VERSION 5.7 ;
  NOWIREEXTENSIONATPIN ON ;
  DIVIDERCHAR "/" ;
  BUSBITCHARS "[]" ;
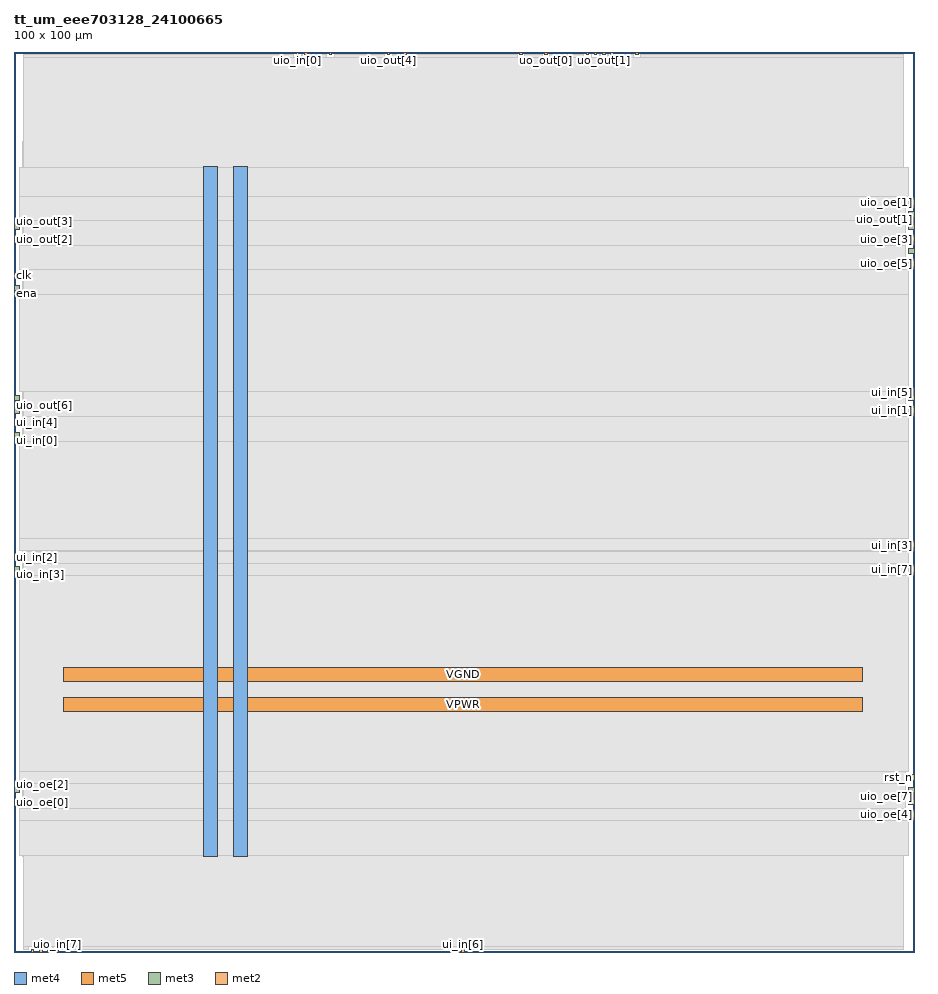
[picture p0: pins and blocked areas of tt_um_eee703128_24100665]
MACRO tt_um_eee703128_24100665
  CLASS BLOCK ;
  FOREIGN tt_um_eee703128_24100665 ;
  ORIGIN 0.000 0.000 ;
  SIZE 100.000 BY 100.000 ;
  PIN VGND
    DIRECTION INOUT ;
    USE GROUND ;
    PORT
      LAYER met4 ;
        RECT 24.340 10.640 25.940 87.280 ;
    END
    PORT
      LAYER met5 ;
        RECT 5.520 30.030 94.300 31.630 ;
    END
  END VGND
  PIN VPWR
    DIRECTION INOUT ;
    USE POWER ;
    PORT
      LAYER met4 ;
        RECT 21.040 10.640 22.640 87.280 ;
    END
    PORT
      LAYER met5 ;
        RECT 5.520 26.730 94.300 28.330 ;
    END
  END VPWR
  PIN clk
    DIRECTION INPUT ;
    USE SIGNAL ;
    ANTENNAGATEAREA 0.852000 ;
    PORT
      LAYER met3 ;
        RECT 0.000 74.840 0.600 75.440 ;
    END
  END clk
  PIN ena
    DIRECTION INPUT ;
    USE SIGNAL ;
    ANTENNAGATEAREA 0.213000 ;
    PORT
      LAYER met3 ;
        RECT 0.000 73.480 0.600 74.080 ;
    END
  END ena
  PIN rst_n
    DIRECTION INPUT ;
    USE SIGNAL ;
    ANTENNAGATEAREA 0.213000 ;
    PORT
      LAYER met3 ;
        RECT 99.400 19.080 100.000 19.680 ;
    END
  END rst_n
  PIN ui_in[0]
    DIRECTION INPUT ;
    USE SIGNAL ;
    ANTENNAGATEAREA 0.213000 ;
    PORT
      LAYER met3 ;
        RECT 0.000 57.160 0.600 57.760 ;
    END
  END ui_in[0]
  PIN ui_in[1]
    DIRECTION INPUT ;
    USE SIGNAL ;
    ANTENNAGATEAREA 0.213000 ;
    PORT
      LAYER met3 ;
        RECT 99.400 59.880 100.000 60.480 ;
    END
  END ui_in[1]
  PIN ui_in[2]
    DIRECTION INPUT ;
    USE SIGNAL ;
    ANTENNAGATEAREA 0.213000 ;
    PORT
      LAYER met3 ;
        RECT 0.000 43.560 0.600 44.160 ;
    END
  END ui_in[2]
  PIN ui_in[3]
    DIRECTION INPUT ;
    USE SIGNAL ;
    ANTENNAGATEAREA 0.213000 ;
    PORT
      LAYER met3 ;
        RECT 99.400 44.920 100.000 45.520 ;
    END
  END ui_in[3]
  PIN ui_in[4]
    DIRECTION INPUT ;
    USE SIGNAL ;
    ANTENNAGATEAREA 0.213000 ;
    PORT
      LAYER met3 ;
        RECT 0.000 58.520 0.600 59.120 ;
    END
  END ui_in[4]
  PIN ui_in[5]
    DIRECTION INPUT ;
    USE SIGNAL ;
    ANTENNAGATEAREA 0.213000 ;
    PORT
      LAYER met3 ;
        RECT 99.400 61.240 100.000 61.840 ;
    END
  END ui_in[5]
  PIN ui_in[6]
    DIRECTION INPUT ;
    USE SIGNAL ;
    ANTENNAGATEAREA 0.213000 ;
    PORT
      LAYER met2 ;
        RECT 49.770 0.000 50.050 0.280 ;
    END
  END ui_in[6]
  PIN ui_in[7]
    DIRECTION INPUT ;
    USE SIGNAL ;
    ANTENNAGATEAREA 0.213000 ;
    PORT
      LAYER met3 ;
        RECT 99.400 42.200 100.000 42.800 ;
    END
  END ui_in[7]
  PIN uio_in[0]
    DIRECTION INPUT ;
    USE SIGNAL ;
    ANTENNAGATEAREA 0.213000 ;
    PORT
      LAYER met2 ;
        RECT 31.370 99.720 31.650 100.000 ;
    END
  END uio_in[0]
  PIN uio_in[1]
    DIRECTION INPUT ;
    USE SIGNAL ;
    ANTENNAGATEAREA 0.213000 ;
    PORT
      LAYER met2 ;
        RECT 32.290 99.720 32.570 100.000 ;
    END
  END uio_in[1]
  PIN uio_in[2]
    DIRECTION INPUT ;
    USE SIGNAL ;
    ANTENNAGATEAREA 0.213000 ;
    PORT
      LAYER met2 ;
        RECT 35.050 99.720 35.330 100.000 ;
    END
  END uio_in[2]
  PIN uio_in[3]
    DIRECTION INPUT ;
    USE SIGNAL ;
    ANTENNAGATEAREA 0.213000 ;
    PORT
      LAYER met3 ;
        RECT 0.000 42.200 0.600 42.800 ;
    END
  END uio_in[3]
  PIN uio_in[4]
    DIRECTION INPUT ;
    USE SIGNAL ;
    PORT
      LAYER met2 ;
        RECT 1.930 0.000 2.210 0.280 ;
    END
  END uio_in[4]
  PIN uio_in[5]
    DIRECTION INPUT ;
    USE SIGNAL ;
    PORT
      LAYER met2 ;
        RECT 2.850 0.000 3.130 0.280 ;
    END
  END uio_in[5]
  PIN uio_in[6]
    DIRECTION INPUT ;
    USE SIGNAL ;
    PORT
      LAYER met2 ;
        RECT 3.770 0.000 4.050 0.280 ;
    END
  END uio_in[6]
  PIN uio_in[7]
    DIRECTION INPUT ;
    USE SIGNAL ;
    PORT
      LAYER met2 ;
        RECT 4.690 0.000 4.970 0.280 ;
    END
  END uio_in[7]
  PIN uio_oe[0]
    DIRECTION OUTPUT ;
    USE SIGNAL ;
    PORT
      LAYER met3 ;
        RECT 0.000 16.360 0.600 16.960 ;
    END
  END uio_oe[0]
  PIN uio_oe[1]
    DIRECTION OUTPUT ;
    USE SIGNAL ;
    PORT
      LAYER met3 ;
        RECT 99.400 83.000 100.000 83.600 ;
    END
  END uio_oe[1]
  PIN uio_oe[2]
    DIRECTION OUTPUT ;
    USE SIGNAL ;
    PORT
      LAYER met3 ;
        RECT 0.000 17.720 0.600 18.320 ;
    END
  END uio_oe[2]
  PIN uio_oe[3]
    DIRECTION OUTPUT ;
    USE SIGNAL ;
    PORT
      LAYER met3 ;
        RECT 99.400 78.920 100.000 79.520 ;
    END
  END uio_oe[3]
  PIN uio_oe[4]
    DIRECTION OUTPUT ;
    USE SIGNAL ;
    PORT
      LAYER met3 ;
        RECT 99.400 15.000 100.000 15.600 ;
    END
  END uio_oe[4]
  PIN uio_oe[5]
    DIRECTION OUTPUT ;
    USE SIGNAL ;
    PORT
      LAYER met3 ;
        RECT 99.400 76.200 100.000 76.800 ;
    END
  END uio_oe[5]
  PIN uio_oe[6]
    DIRECTION OUTPUT ;
    USE SIGNAL ;
    PORT
      LAYER met3 ;
        RECT 99.400 77.560 100.000 78.160 ;
    END
  END uio_oe[6]
  PIN uio_oe[7]
    DIRECTION OUTPUT ;
    USE SIGNAL ;
    PORT
      LAYER met3 ;
        RECT 99.400 16.360 100.000 16.960 ;
    END
  END uio_oe[7]
  PIN uio_out[0]
    DIRECTION OUTPUT ;
    USE SIGNAL ;
    PORT
      LAYER met3 ;
        RECT 99.400 17.720 100.000 18.320 ;
    END
  END uio_out[0]
  PIN uio_out[1]
    DIRECTION OUTPUT ;
    USE SIGNAL ;
    PORT
      LAYER met3 ;
        RECT 99.400 81.640 100.000 82.240 ;
    END
  END uio_out[1]
  PIN uio_out[2]
    DIRECTION OUTPUT ;
    USE SIGNAL ;
    PORT
      LAYER met3 ;
        RECT 0.000 78.920 0.600 79.520 ;
    END
  END uio_out[2]
  PIN uio_out[3]
    DIRECTION OUTPUT ;
    USE SIGNAL ;
    PORT
      LAYER met3 ;
        RECT 0.000 80.280 0.600 80.880 ;
    END
  END uio_out[3]
  PIN uio_out[4]
    DIRECTION OUTPUT ;
    USE SIGNAL ;
    ANTENNADIFFAREA 0.702900 ;
    PORT
      LAYER met2 ;
        RECT 41.490 99.720 41.770 100.000 ;
    END
  END uio_out[4]
  PIN uio_out[5]
    DIRECTION OUTPUT ;
    USE SIGNAL ;
    ANTENNADIFFAREA 0.702900 ;
    PORT
      LAYER met3 ;
        RECT 0.000 61.240 0.600 61.840 ;
    END
  END uio_out[5]
  PIN uio_out[6]
    DIRECTION OUTPUT ;
    USE SIGNAL ;
    ANTENNADIFFAREA 0.702900 ;
    PORT
      LAYER met3 ;
        RECT 0.000 59.880 0.600 60.480 ;
    END
  END uio_out[6]
  PIN uio_out[7]
    DIRECTION OUTPUT ;
    USE SIGNAL ;
    ANTENNADIFFAREA 0.702900 ;
    PORT
      LAYER met2 ;
        RECT 43.330 99.720 43.610 100.000 ;
    END
  END uio_out[7]
  PIN uo_out[0]
    DIRECTION OUTPUT ;
    USE SIGNAL ;
    ANTENNADIFFAREA 0.702900 ;
    PORT
      LAYER met2 ;
        RECT 58.970 99.720 59.250 100.000 ;
    END
  END uo_out[0]
  PIN uo_out[1]
    DIRECTION OUTPUT ;
    USE SIGNAL ;
    ANTENNADIFFAREA 0.702900 ;
    PORT
      LAYER met2 ;
        RECT 65.410 99.720 65.690 100.000 ;
    END
  END uo_out[1]
  PIN uo_out[2]
    DIRECTION OUTPUT ;
    USE SIGNAL ;
    ANTENNADIFFAREA 0.702900 ;
    PORT
      LAYER met2 ;
        RECT 56.210 99.720 56.490 100.000 ;
    END
  END uo_out[2]
  PIN uo_out[3]
    DIRECTION OUTPUT ;
    USE SIGNAL ;
    ANTENNADIFFAREA 0.702900 ;
    PORT
      LAYER met2 ;
        RECT 66.330 99.720 66.610 100.000 ;
    END
  END uo_out[3]
  PIN uo_out[4]
    DIRECTION OUTPUT ;
    USE SIGNAL ;
    ANTENNADIFFAREA 0.702900 ;
    PORT
      LAYER met2 ;
        RECT 63.570 99.720 63.850 100.000 ;
    END
  END uo_out[4]
  PIN uo_out[5]
    DIRECTION OUTPUT ;
    USE SIGNAL ;
    ANTENNADIFFAREA 0.702900 ;
    PORT
      LAYER met2 ;
        RECT 64.490 99.720 64.770 100.000 ;
    END
  END uo_out[5]
  PIN uo_out[6]
    DIRECTION OUTPUT ;
    USE SIGNAL ;
    ANTENNADIFFAREA 0.702900 ;
    PORT
      LAYER met2 ;
        RECT 69.090 99.720 69.370 100.000 ;
    END
  END uo_out[6]
  PIN uo_out[7]
    DIRECTION OUTPUT ;
    USE SIGNAL ;
    PORT
      LAYER met3 ;
        RECT 99.400 80.280 100.000 80.880 ;
    END
  END uo_out[7]
  OBS
      LAYER nwell ;
        RECT 5.330 10.795 94.490 87.125 ;
      LAYER li1 ;
        RECT 5.520 10.795 94.300 87.125 ;
      LAYER met1 ;
        RECT 0.990 10.640 98.830 90.060 ;
      LAYER met2 ;
        RECT 1.010 99.440 31.090 99.720 ;
        RECT 31.930 99.440 32.010 99.720 ;
        RECT 32.850 99.440 34.770 99.720 ;
        RECT 35.610 99.440 41.210 99.720 ;
        RECT 42.050 99.440 43.050 99.720 ;
        RECT 43.890 99.440 55.930 99.720 ;
        RECT 56.770 99.440 58.690 99.720 ;
        RECT 59.530 99.440 63.290 99.720 ;
        RECT 64.130 99.440 64.210 99.720 ;
        RECT 65.050 99.440 65.130 99.720 ;
        RECT 65.970 99.440 66.050 99.720 ;
        RECT 66.890 99.440 68.810 99.720 ;
        RECT 69.650 99.440 98.810 99.720 ;
        RECT 1.010 0.560 98.810 99.440 ;
        RECT 1.010 0.280 1.650 0.560 ;
        RECT 2.490 0.280 2.570 0.560 ;
        RECT 3.410 0.280 3.490 0.560 ;
        RECT 4.330 0.280 4.410 0.560 ;
        RECT 5.250 0.280 49.490 0.560 ;
        RECT 50.330 0.280 98.810 0.560 ;
      LAYER met3 ;
        RECT 0.600 84.000 99.400 87.205 ;
        RECT 0.600 81.280 99.000 84.000 ;
        RECT 1.000 78.520 99.000 81.280 ;
        RECT 0.600 75.840 99.000 78.520 ;
        RECT 1.000 75.800 99.000 75.840 ;
        RECT 1.000 73.080 99.400 75.800 ;
        RECT 0.600 62.240 99.400 73.080 ;
        RECT 1.000 59.480 99.000 62.240 ;
        RECT 1.000 56.760 99.400 59.480 ;
        RECT 0.600 45.920 99.400 56.760 ;
        RECT 0.600 44.560 99.000 45.920 ;
        RECT 1.000 44.520 99.000 44.560 ;
        RECT 1.000 43.200 99.400 44.520 ;
        RECT 1.000 41.800 99.000 43.200 ;
        RECT 0.600 20.080 99.400 41.800 ;
        RECT 0.600 18.720 99.000 20.080 ;
        RECT 1.000 15.960 99.000 18.720 ;
        RECT 0.600 14.600 99.000 15.960 ;
        RECT 0.600 10.715 99.400 14.600 ;
  END
END tt_um_eee703128_24100665
END LIBRARY

